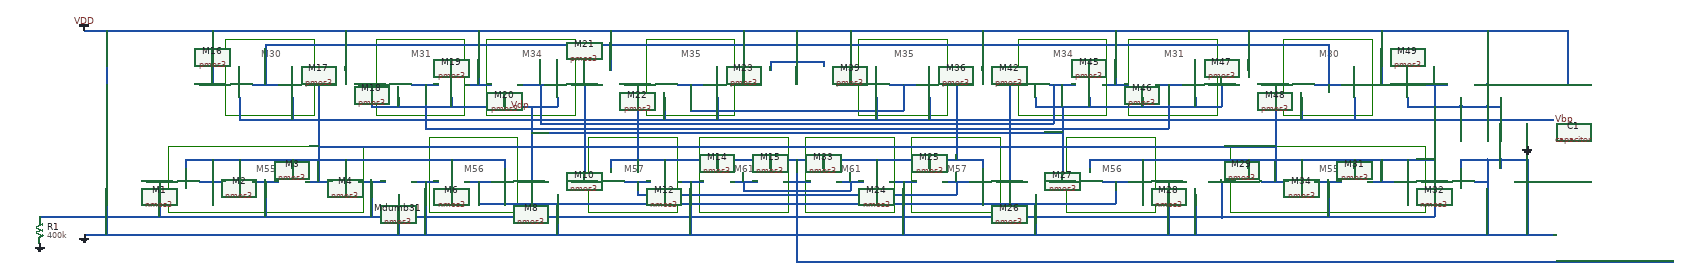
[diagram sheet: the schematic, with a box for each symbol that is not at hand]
v {xschem version=2.9.9 file_version=1.2 }
G {}
K {}
V {}
S {}
E {}
L 4 -700 -70 -500 -70 {}
L 4 -500 -240 -500 -70 {}
L 4 -700 -240 -500 -240 {}
L 4 -700 -240 -700 -70 {}
L 4 500 -70 700 -70 {}
L 4 700 -240 700 -70 {}
L 4 500 -240 700 -240 {}
L 4 500 -240 500 -70 {}
L 4 750 -70 950 -70 {}
L 4 950 -240 950 -70 {}
L 4 750 -240 950 -240 {}
L 4 750 -240 750 -70 {}
L 4 -950 -70 -750 -70 {}
L 4 -750 -240 -750 -70 {}
L 4 -950 -240 -750 -240 {}
L 4 -950 -240 -950 -70 {}
L 4 -1290 -70 -1090 -70 {}
L 4 -1090 -240 -1090 -70 {}
L 4 -1290 -240 -1090 -240 {}
L 4 -1290 -240 -1290 -70 {}
L 4 140 -70 340 -70 {}
L 4 340 -240 340 -70 {}
L 4 140 -240 340 -240 {}
L 4 140 -240 140 -70 {}
L 4 20 150 220 150 {}
L 4 220 -20 220 150 {}
L 4 20 -20 220 -20 {}
L 4 20 -20 20 150 {}
L 4 -220 150 -20 150 {}
L 4 -20 -20 -20 150 {}
L 4 -220 -20 -20 -20 {}
L 4 -220 -20 -220 150 {}
L 4 -470 150 -270 150 {}
L 4 -270 -20 -270 150 {}
L 4 -470 -20 -270 -20 {}
L 4 -470 -20 -470 150 {}
L 4 1100 -70 1300 -70 {}
L 4 1300 -240 1300 -70 {}
L 4 1100 -240 1300 -240 {}
L 4 1100 -240 1100 -70 {}
L 4 -1420 0 -1420 150 {}
L 4 -1420 150 -980 150 {}
L 4 -980 0 -980 150 {}
L 4 -1420 0 -980 0 {}
L 4 980 0 980 150 {}
L 4 980 150 1420 150 {}
L 4 1420 0 1420 150 {}
L 4 980 0 1420 0 {}
L 4 -830 150 -630 150 {}
L 4 -630 -20 -630 150 {}
L 4 -830 -20 -630 -20 {}
L 4 -830 -20 -830 150 {}
L 4 610 150 810 150 {}
L 4 810 -20 810 150 {}
L 4 610 -20 810 -20 {}
L 4 610 -20 610 150 {}
L 4 -340 -70 -140 -70 {}
L 4 -140 -240 -140 -70 {}
L 4 -340 -240 -140 -240 {}
L 4 -340 -240 -340 -70 {}
L 4 260 150 460 150 {}
L 4 460 -20 460 150 {}
L 4 260 -20 460 -20 {}
L 4 260 -20 260 150 {}
T {M34} -620 -220 0 0 0.4 0.4 {}
T {M34} 580 -220 0 0 0.4 0.4 {}
T {M31} 830 -220 0 0 0.4 0.4 {}
T {M31} -870 -220 0 0 0.4 0.4 {}
T {M30} -1210 -220 0 0 0.4 0.4 {}
T {M35} 220 -220 0 0 0.4 0.4 {}
T {M30} 1180 -220 0 0 0.4 0.4 {}
T {M55} -1220 40 0 0 0.4 0.4 {}
T {M55} 1180 40 0 0 0.4 0.4 {}
T {M56} -750 40 0 0 0.4 0.4 {}
T {M56} 690 40 0 0 0.4 0.4 {}
T {M35} -260 -220 0 0 0.4 0.4 {}
T {M57} 340 40 0 0 0.4 0.4 {}
T {M57} -390 40 0 0 0.4 0.4 {}
T {M61} -140 40 0 0 0.4 0.4 {}
T {M61} 100 40 0 0 0.4 0.4 {}
N -1020 30 -1020 50 { lab=#net1}
N -1140 30 -1140 50 { lab=#net1}
N -1260 30 -1260 50 { lab=#net1}
N -1380 30 -1380 50 { lab=#net1}
N -1350 80 -1290 80 { lab=#net1}
N -1230 80 -1170 80 { lab=#net2}
N -1110 80 -1050 80 { lab=#net1}
N -1230 -140 -1170 -140 { lab=#net3}
N -870 -140 -810 -140 { lab=#net4}
N -630 -140 -570 -140 { lab=#net5}
N -270 -140 -210 -140 { lab=#net6}
N -900 -110 -900 -90 { lab=Vdp}
N -540 -110 -540 -90 { lab=Vdp}
N -780 -110 -780 -90 { lab=Vdp}
N -660 -110 -660 -90 { lab=Vdp}
N -1260 -110 -1260 -60 { lab=Vbp}
N -180 -110 -180 -60 { lab=Vbp}
N -300 -110 -300 -60 { lab=Vbp}
N -1140 -110 -1140 -60 { lab=Vbp}
N -1320 -260 -1320 -140 { lab=VDD}
N -120 -260 -120 -140 { lab=VDD}
N -750 -140 -690 -140 { lab=VDD}
N -720 -260 -720 -140 { lab=VDD}
N -780 30 -780 50 { lab=#net1}
N -660 30 -660 50 { lab=#net1}
N -750 80 -690 80 { lab=#net7}
N -390 80 -330 80 { lab=#net8}
N -150 80 -90 80 { lab=#net9}
N -960 80 -960 160 { lab=#net2}
N -420 30 -420 50 { lab=#net10}
N -60 30 -60 50 { lab=#net10}
N -180 30 -180 50 { lab=#net10}
N -300 30 -300 50 { lab=#net10}
N -270 80 -210 80 { lab=GND}
N -240 80 -240 200 { lab=GND}
N -840 80 -840 200 { lab=GND}
N 0 30 0 80 { lab=#net10}
N -480 -60 -480 80 { lab=Vbp}
N -1110 -140 -1050 -140 { lab=#net1}
N -990 -140 -930 -140 { lab=Vdp}
N -1080 -140 -1080 30 { lab=#net1}
N -390 -140 -330 -140 { lab=#net10}
N -360 -140 -360 30 { lab=#net10}
N -510 -140 -450 -140 { lab=Vbp}
N -480 -140 -480 -60 { lab=Vbp}
N -870 80 -810 80 { lab=GND}
N -990 80 -930 80 { lab=#net2}
N -630 80 -570 80 { lab=Vdp}
N -600 -90 -600 80 { lab=Vdp}
N -510 80 -450 80 { lab=Vbp}
N 60 30 60 50 { lab=#net10}
N 180 30 180 50 { lab=#net10}
N 300 30 300 50 { lab=#net10}
N 420 30 420 50 { lab=#net10}
N -30 80 30 80 { lab=#net10}
N -420 30 420 30 { lab=#net10}
N 90 80 150 80 { lab=#net9}
N 210 80 270 80 { lab=GND}
N 330 80 390 80 { lab=#net8}
N 240 80 240 200 { lab=GND}
N -150 -140 -90 -140 { lab=VDD}
N 0 -260 0 -140 { lab=VDD}
N 90 -140 150 -140 { lab=VDD}
N 120 -260 120 -140 { lab=VDD}
N 180 -110 180 -60 { lab=Vbp}
N 300 -110 300 -60 { lab=Vbp}
N 1260 -110 1260 -60 { lab=Vbp}
N 1140 -110 1140 -60 { lab=Vbp}
N 540 -110 540 -90 { lab=Vdp}
N 660 -110 660 -90 { lab=Vdp}
N 780 -110 780 -90 { lab=Vdp}
N 900 -110 900 -90 { lab=Vdp}
N -960 -140 -960 -90 { lab=Vdp}
N -960 -90 -540 -90 { lab=Vdp}
N 210 -140 270 -140 { lab=#net6}
N 330 -140 390 -140 { lab=#net10}
N 450 -140 510 -140 { lab=Vbp}
N 570 -140 630 -140 { lab=#net5}
N 690 -140 750 -140 { lab=VDD}
N 810 -140 870 -140 { lab=#net4}
N 930 -140 990 -140 { lab=Vdp}
N 1050 -140 1110 -140 { lab=#net1}
N 1170 -140 1230 -140 { lab=#net3}
N 450 80 510 80 { lab=Vbp}
N 570 80 630 80 { lab=Vdp}
N 690 80 750 80 { lab=#net7}
N 810 80 870 80 { lab=GND}
N 930 80 990 80 { lab=#net2}
N 1050 80 1110 80 { lab=#net1}
N 1170 80 1230 80 { lab=#net2}
N 1290 80 1350 80 { lab=#net1}
N 1380 30 1380 50 { lab=#net1}
N 1020 30 1020 50 { lab=#net1}
N 1140 30 1140 50 { lab=#net1}
N 1260 30 1260 50 { lab=#net1}
N -1260 -60 1260 -60 { lab=Vbp}
N 960 -140 960 -90 { lab=Vdp}
N 540 -90 960 -90 { lab=Vdp}
N 360 -140 360 30 { lab=#net10}
N 480 -140 480 -60 { lab=Vbp}
N 480 -60 480 80 { lab=Vbp}
N 840 80 840 200 { lab=GND}
N 960 80 960 160 { lab=#net2}
N 600 -90 600 80 { lab=Vdp}
N 660 30 660 50 { lab=#net1}
N 780 30 780 50 { lab=#net1}
N 660 30 1440 30 { lab=#net1}
N 1320 -260 1320 -140 { lab=VDD}
N 1080 -140 1080 30 { lab=#net1}
N -600 -30 600 -30 { lab=Vdp}
N -1080 0 1080 0 { lab=#net1}
N 0 80 0 260 { lab=#net10}
N -1350 -140 -1290 -140 { lab=VDD}
N -1470 80 -1410 80 { lab=#net2}
N 1410 80 1470 80 { lab=#net2}
N 1500 30 1500 50 { lab=GND}
N 1500 30 1560 30 { lab=GND}
N 1560 30 1560 80 { lab=GND}
N 1530 80 1560 80 { lab=GND}
N 1560 80 1560 200 { lab=GND}
N 1290 -140 1350 -140 { lab=VDD}
N 1380 -110 1380 -90 { lab=VDD}
N 1380 -90 1500 -90 { lab=VDD}
N 1500 -110 1500 -90 { lab=VDD}
N 1410 -140 1470 -140 { lab=VDD}
N 1440 -140 1440 -90 { lab=VDD}
N 1530 -140 1560 -140 { lab=VDD}
N 1560 -260 1560 -140 { lab=VDD}
N -1610 160 960 160 { lab=#net2}
N -1610 200 1710 200 { lab=GND}
N 0 260 1710 260 { lab=#net10}
N 1260 -60 1710 -60 { lab=Vbp}
N -1610 -260 1710 -260 { lab=VDD}
N -900 110 -900 200 { lab=GND}
N -1020 -260 -1020 -170 { lab=VDD}
N -60 -190 -60 -170 { lab=VDD}
N 60 -190 60 -180 { lab=VDD}
N -60 -190 0 -190 { lab=VDD}
N 0 -190 60 -190 { lab=VDD}
N -420 -260 -420 -170 { lab=VDD}
N 420 -260 420 -170 { lab=VDD}
N 1020 -260 1020 -170 { lab=VDD}
N -540 110 -540 200 { lab=GND}
N -1560 -260 -1560 -140 { lab=VDD}
N -1560 80 -1560 200 { lab=GND}
N 1500 -90 1560 -90 { lab=VDD}
N 1560 -140 1560 -90 { lab=VDD}
N 900 110 900 200 { lab=GND}
N 540 110 540 200 { lab=GND}
N -1200 80 -1200 150 { lab=#net2}
N -1200 150 -1200 160 { lab=#net2}
N -1080 30 -1080 80 { lab=#net1}
N -1320 30 -1320 80 { lab=#net1}
N -1440 80 -1440 160 { lab=#net2}
N -1380 30 -660 30 { lab=#net1}
N 960 160 1440 160 { lab=#net2}
N 1440 80 1440 160 { lab=#net2}
N 1200 80 1200 160 { lab=#net2}
N 1080 30 1080 80 { lab=#net1}
N 1320 30 1320 80 { lab=#net1}
N 1710 260 1980 260 { lab=#net10}
N -1650 160 -1610 160 { lab=#net2}
N -1710 160 -1660 160 { lab=#net2}
N -840 -140 -840 -40 { lab=#net4}
N -840 -40 840 -40 { lab=#net4}
N 840 -140 840 -40 { lab=#net4}
N -580 -140 -580 -50 { lab=#net5}
N -580 -50 580 -50 { lab=#net5}
N 580 -140 580 -50 { lab=#net5}
N -240 -140 -240 -80 { lab=#net6}
N -240 -80 240 -80 { lab=#net6}
N 240 -140 240 -80 { lab=#net6}
N -1200 -230 -1200 -140 { lab=#net3}
N -1200 -230 1200 -230 { lab=#net3}
N 1200 -230 1200 -140 { lab=#net3}
N -720 80 -720 130 { lab=#net7}
N -720 130 720 130 { lab=#net7}
N 720 80 720 130 { lab=#net7}
N 360 80 360 110 { lab=#net8}
N -350 110 360 110 { lab=#net8}
N -360 110 -350 110 { lab=#net8}
N -360 80 -360 110 { lab=#net8}
N -120 80 -120 100 { lab=#net9}
N -120 100 120 100 { lab=#net9}
N 120 80 120 100 { lab=#net9}
N 720 -260 720 -140 { lab=VDD}
N 1560 30 1590 30 { lab=GND}
N 1590 30 1590 40 { lab=GND}
N 1590 40 1590 50 { lab=GND}
N 1590 30 1620 30 { lab=GND}
N 1620 80 1650 80 { lab=GND}
N 1620 30 1650 30 { lab=GND}
N 1650 30 1650 200 { lab=GND}
N -1660 160 -1650 160 { lab=#net2}
N 1590 -110 1590 -90 { lab=VDD}
N 1620 -140 1680 -140 { lab=VDD}
N 1740 -260 1740 -140 { lab=VDD}
N 1710 -260 1740 -260 { lab=VDD}
N 1560 -90 1590 -90 { lab=VDD}
N 1680 -140 1740 -140 { lab=VDD}
C {madvlsi/nmos3.sym} -1380 80 1 0 {name=M1
L=4.0
W=16
body=GND
nf=1
mult=1
ad="'int((nf+1)/2) * W/nf * 0.29'" 
pd="'2*int((nf+1)/2) * (W/nf + 0.29)'"
as="'int((nf+2)/2) * W/nf * 0.29'" 
ps="'2*int((nf+2)/2) * (W/nf + 0.29)'"
nrd="'0.29 / W'" nrs="'0.29 / W'"
sa=0 sb=0 sd=0
model=nfet_01v8
spiceprefix=X
}
C {madvlsi/nmos3.sym} -1260 80 1 0 {name=M2
L=4.0
W=16
body=GND
nf=1
mult=1
ad="'int((nf+1)/2) * W/nf * 0.29'" 
pd="'2*int((nf+1)/2) * (W/nf + 0.29)'"
as="'int((nf+2)/2) * W/nf * 0.29'" 
ps="'2*int((nf+2)/2) * (W/nf + 0.29)'"
nrd="'0.29 / W'" nrs="'0.29 / W'"
sa=0 sb=0 sd=0
model=nfet_01v8
spiceprefix=X
}
C {madvlsi/nmos3.sym} -1140 80 1 0 {name=M3
L=4.0
W=16
body=GND
nf=1
mult=1
ad="'int((nf+1)/2) * W/nf * 0.29'" 
pd="'2*int((nf+1)/2) * (W/nf + 0.29)'"
as="'int((nf+2)/2) * W/nf * 0.29'" 
ps="'2*int((nf+2)/2) * (W/nf + 0.29)'"
nrd="'0.29 / W'" nrs="'0.29 / W'"
sa=0 sb=0 sd=0
model=nfet_01v8
spiceprefix=X
}
C {madvlsi/nmos3.sym} -1020 80 1 0 {name=M4
L=4.0
W=16
body=GND
nf=1
mult=1
ad="'int((nf+1)/2) * W/nf * 0.29'" 
pd="'2*int((nf+1)/2) * (W/nf + 0.29)'"
as="'int((nf+2)/2) * W/nf * 0.29'" 
ps="'2*int((nf+2)/2) * (W/nf + 0.29)'"
nrd="'0.29 / W'" nrs="'0.29 / W'"
sa=0 sb=0 sd=0
model=nfet_01v8
spiceprefix=X
}
C {madvlsi/nmos3.sym} -780 80 1 0 {name=M6
L=4.0
W=16
body=GND
nf=1
mult=1
ad="'int((nf+1)/2) * W/nf * 0.29'" 
pd="'2*int((nf+1)/2) * (W/nf + 0.29)'"
as="'int((nf+2)/2) * W/nf * 0.29'" 
ps="'2*int((nf+2)/2) * (W/nf + 0.29)'"
nrd="'0.29 / W'" nrs="'0.29 / W'"
sa=0 sb=0 sd=0
model=nfet_01v8
spiceprefix=X
}
C {madvlsi/nmos3.sym} -660 80 1 0 {name=M8
L=4.0
W=16
body=GND
nf=1
mult=1
ad="'int((nf+1)/2) * W/nf * 0.29'" 
pd="'2*int((nf+1)/2) * (W/nf + 0.29)'"
as="'int((nf+2)/2) * W/nf * 0.29'" 
ps="'2*int((nf+2)/2) * (W/nf + 0.29)'"
nrd="'0.29 / W'" nrs="'0.29 / W'"
sa=0 sb=0 sd=0
model=nfet_01v8
spiceprefix=X
}
C {madvlsi/nmos3.sym} -420 80 1 0 {name=M10
L=4.0
W=16
body=GND
nf=1
mult=1
ad="'int((nf+1)/2) * W/nf * 0.29'" 
pd="'2*int((nf+1)/2) * (W/nf + 0.29)'"
as="'int((nf+2)/2) * W/nf * 0.29'" 
ps="'2*int((nf+2)/2) * (W/nf + 0.29)'"
nrd="'0.29 / W'" nrs="'0.29 / W'"
sa=0 sb=0 sd=0
model=nfet_01v8
spiceprefix=X
}
C {madvlsi/nmos3.sym} -300 80 1 0 {name=M12
L=4.0
W=16
body=GND
nf=1
mult=1
ad="'int((nf+1)/2) * W/nf * 0.29'" 
pd="'2*int((nf+1)/2) * (W/nf + 0.29)'"
as="'int((nf+2)/2) * W/nf * 0.29'" 
ps="'2*int((nf+2)/2) * (W/nf + 0.29)'"
nrd="'0.29 / W'" nrs="'0.29 / W'"
sa=0 sb=0 sd=0
model=nfet_01v8
spiceprefix=X
}
C {madvlsi/nmos3.sym} -180 80 1 0 {name=M14
L=4.0
W=16
body=GND
nf=1
mult=1
ad="'int((nf+1)/2) * W/nf * 0.29'" 
pd="'2*int((nf+1)/2) * (W/nf + 0.29)'"
as="'int((nf+2)/2) * W/nf * 0.29'" 
ps="'2*int((nf+2)/2) * (W/nf + 0.29)'"
nrd="'0.29 / W'" nrs="'0.29 / W'"
sa=0 sb=0 sd=0
model=nfet_01v8
spiceprefix=X
}
C {madvlsi/nmos3.sym} -60 80 1 0 {name=M15
L=4.0
W=16
body=GND
nf=1
mult=1
ad="'int((nf+1)/2) * W/nf * 0.29'" 
pd="'2*int((nf+1)/2) * (W/nf + 0.29)'"
as="'int((nf+2)/2) * W/nf * 0.29'" 
ps="'2*int((nf+2)/2) * (W/nf + 0.29)'"
nrd="'0.29 / W'" nrs="'0.29 / W'"
sa=0 sb=0 sd=0
model=nfet_01v8
spiceprefix=X
}
C {madvlsi/pmos3.sym} -1260 -140 1 1 {name=M16
L=4.0
W=16
body=VDD
nf=1
mult=1
ad="'int((nf+1)/2) * W/nf * 0.29'" 
pd="'2*int((nf+1)/2) * (W/nf + 0.29)'"
as="'int((nf+2)/2) * W/nf * 0.29'" 
ps="'2*int((nf+2)/2) * (W/nf + 0.29)'"
nrd="'0.29 / W'" nrs="'0.29 / W'"
sa=0 sb=0 sd=0
model=pfet_01v8
spiceprefix=X
}
C {madvlsi/pmos3.sym} -1140 -140 1 1 {name=M17
L=4.0
W=16
body=VDD
nf=1
mult=1
ad="'int((nf+1)/2) * W/nf * 0.29'" 
pd="'2*int((nf+1)/2) * (W/nf + 0.29)'"
as="'int((nf+2)/2) * W/nf * 0.29'" 
ps="'2*int((nf+2)/2) * (W/nf + 0.29)'"
nrd="'0.29 / W'" nrs="'0.29 / W'"
sa=0 sb=0 sd=0
model=pfet_01v8
spiceprefix=X
}
C {madvlsi/pmos3.sym} -900 -140 1 1 {name=M18
L=4.0
W=16
body=VDD
nf=1
mult=1
ad="'int((nf+1)/2) * W/nf * 0.29'" 
pd="'2*int((nf+1)/2) * (W/nf + 0.29)'"
as="'int((nf+2)/2) * W/nf * 0.29'" 
ps="'2*int((nf+2)/2) * (W/nf + 0.29)'"
nrd="'0.29 / W'" nrs="'0.29 / W'"
sa=0 sb=0 sd=0
model=pfet_01v8
spiceprefix=X
}
C {madvlsi/pmos3.sym} -780 -140 1 1 {name=M19
L=4.0
W=16
body=VDD
nf=1
mult=1
ad="'int((nf+1)/2) * W/nf * 0.29'" 
pd="'2*int((nf+1)/2) * (W/nf + 0.29)'"
as="'int((nf+2)/2) * W/nf * 0.29'" 
ps="'2*int((nf+2)/2) * (W/nf + 0.29)'"
nrd="'0.29 / W'" nrs="'0.29 / W'"
sa=0 sb=0 sd=0
model=pfet_01v8
spiceprefix=X
}
C {madvlsi/pmos3.sym} -660 -140 1 1 {name=M20
L=4.0
W=16
body=VDD
nf=1
mult=1
ad="'int((nf+1)/2) * W/nf * 0.29'" 
pd="'2*int((nf+1)/2) * (W/nf + 0.29)'"
as="'int((nf+2)/2) * W/nf * 0.29'" 
ps="'2*int((nf+2)/2) * (W/nf + 0.29)'"
nrd="'0.29 / W'" nrs="'0.29 / W'"
sa=0 sb=0 sd=0
model=pfet_01v8
spiceprefix=X
}
C {madvlsi/pmos3.sym} -540 -140 1 1 {name=M21
L=4.0
W=16
body=VDD
nf=1
mult=1
ad="'int((nf+1)/2) * W/nf * 0.29'" 
pd="'2*int((nf+1)/2) * (W/nf + 0.29)'"
as="'int((nf+2)/2) * W/nf * 0.29'" 
ps="'2*int((nf+2)/2) * (W/nf + 0.29)'"
nrd="'0.29 / W'" nrs="'0.29 / W'"
sa=0 sb=0 sd=0
model=pfet_01v8
spiceprefix=X
}
C {madvlsi/pmos3.sym} -300 -140 1 1 {name=M22
L=4.0
W=16
body=VDD
nf=1
mult=1
ad="'int((nf+1)/2) * W/nf * 0.29'" 
pd="'2*int((nf+1)/2) * (W/nf + 0.29)'"
as="'int((nf+2)/2) * W/nf * 0.29'" 
ps="'2*int((nf+2)/2) * (W/nf + 0.29)'"
nrd="'0.29 / W'" nrs="'0.29 / W'"
sa=0 sb=0 sd=0
model=pfet_01v8
spiceprefix=X
}
C {madvlsi/pmos3.sym} -180 -140 1 1 {name=M23
L=4.0
W=16
body=VDD
nf=1
mult=1
ad="'int((nf+1)/2) * W/nf * 0.29'" 
pd="'2*int((nf+1)/2) * (W/nf + 0.29)'"
as="'int((nf+2)/2) * W/nf * 0.29'" 
ps="'2*int((nf+2)/2) * (W/nf + 0.29)'"
nrd="'0.29 / W'" nrs="'0.29 / W'"
sa=0 sb=0 sd=0
model=pfet_01v8
spiceprefix=X
}
C {madvlsi/nmos3.sym} -900 80 3 0 {name=Mdumb31
L=4.0
W=16
body=GND
nf=1
mult=1
ad="'int((nf+1)/2) * W/nf * 0.29'" 
pd="'2*int((nf+1)/2) * (W/nf + 0.29)'"
as="'int((nf+2)/2) * W/nf * 0.29'" 
ps="'2*int((nf+2)/2) * (W/nf + 0.29)'"
nrd="'0.29 / W'" nrs="'0.29 / W'"
sa=0 sb=0 sd=0
model=nfet_01v8
spiceprefix=X
}
C {madvlsi/nmos3.sym} 60 80 1 0 {name=M33
L=4.0
W=16
body=GND
nf=1
mult=1
ad="'int((nf+1)/2) * W/nf * 0.29'" 
pd="'2*int((nf+1)/2) * (W/nf + 0.29)'"
as="'int((nf+2)/2) * W/nf * 0.29'" 
ps="'2*int((nf+2)/2) * (W/nf + 0.29)'"
nrd="'0.29 / W'" nrs="'0.29 / W'"
sa=0 sb=0 sd=0
model=nfet_01v8
spiceprefix=X
}
C {madvlsi/nmos3.sym} 180 80 1 0 {name=M24
L=4.0
W=16
body=GND
nf=1
mult=1
ad="'int((nf+1)/2) * W/nf * 0.29'" 
pd="'2*int((nf+1)/2) * (W/nf + 0.29)'"
as="'int((nf+2)/2) * W/nf * 0.29'" 
ps="'2*int((nf+2)/2) * (W/nf + 0.29)'"
nrd="'0.29 / W'" nrs="'0.29 / W'"
sa=0 sb=0 sd=0
model=nfet_01v8
spiceprefix=X
}
C {madvlsi/nmos3.sym} 300 80 1 0 {name=M25
L=4.0
W=16
body=GND
nf=1
mult=1
ad="'int((nf+1)/2) * W/nf * 0.29'" 
pd="'2*int((nf+1)/2) * (W/nf + 0.29)'"
as="'int((nf+2)/2) * W/nf * 0.29'" 
ps="'2*int((nf+2)/2) * (W/nf + 0.29)'"
nrd="'0.29 / W'" nrs="'0.29 / W'"
sa=0 sb=0 sd=0
model=nfet_01v8
spiceprefix=X
}
C {madvlsi/nmos3.sym} 420 80 1 0 {name=M26
L=4.0
W=16
body=GND
nf=1
mult=1
ad="'int((nf+1)/2) * W/nf * 0.29'" 
pd="'2*int((nf+1)/2) * (W/nf + 0.29)'"
as="'int((nf+2)/2) * W/nf * 0.29'" 
ps="'2*int((nf+2)/2) * (W/nf + 0.29)'"
nrd="'0.29 / W'" nrs="'0.29 / W'"
sa=0 sb=0 sd=0
model=nfet_01v8
spiceprefix=X
}
C {madvlsi/nmos3.sym} 660 80 1 0 {name=M27
L=4.0
W=16
body=GND
nf=1
mult=1
ad="'int((nf+1)/2) * W/nf * 0.29'" 
pd="'2*int((nf+1)/2) * (W/nf + 0.29)'"
as="'int((nf+2)/2) * W/nf * 0.29'" 
ps="'2*int((nf+2)/2) * (W/nf + 0.29)'"
nrd="'0.29 / W'" nrs="'0.29 / W'"
sa=0 sb=0 sd=0
model=nfet_01v8
spiceprefix=X
}
C {madvlsi/nmos3.sym} 780 80 1 0 {name=M28
L=4.0
W=16
body=GND
nf=1
mult=1
ad="'int((nf+1)/2) * W/nf * 0.29'" 
pd="'2*int((nf+1)/2) * (W/nf + 0.29)'"
as="'int((nf+2)/2) * W/nf * 0.29'" 
ps="'2*int((nf+2)/2) * (W/nf + 0.29)'"
nrd="'0.29 / W'" nrs="'0.29 / W'"
sa=0 sb=0 sd=0
model=nfet_01v8
spiceprefix=X
}
C {madvlsi/nmos3.sym} 1020 80 1 0 {name=M29
L=4.0
W=16
body=GND
nf=1
mult=1
ad="'int((nf+1)/2) * W/nf * 0.29'" 
pd="'2*int((nf+1)/2) * (W/nf + 0.29)'"
as="'int((nf+2)/2) * W/nf * 0.29'" 
ps="'2*int((nf+2)/2) * (W/nf + 0.29)'"
nrd="'0.29 / W'" nrs="'0.29 / W'"
sa=0 sb=0 sd=0
model=nfet_01v8
spiceprefix=X
}
C {madvlsi/nmos3.sym} 1140 80 1 0 {name=M34
L=4.0
W=16
body=GND
nf=1
mult=1
ad="'int((nf+1)/2) * W/nf * 0.29'" 
pd="'2*int((nf+1)/2) * (W/nf + 0.29)'"
as="'int((nf+2)/2) * W/nf * 0.29'" 
ps="'2*int((nf+2)/2) * (W/nf + 0.29)'"
nrd="'0.29 / W'" nrs="'0.29 / W'"
sa=0 sb=0 sd=0
model=nfet_01v8
spiceprefix=X
}
C {madvlsi/nmos3.sym} 1260 80 1 0 {name=M31
L=4.0
W=16
body=GND
nf=1
mult=1
ad="'int((nf+1)/2) * W/nf * 0.29'" 
pd="'2*int((nf+1)/2) * (W/nf + 0.29)'"
as="'int((nf+2)/2) * W/nf * 0.29'" 
ps="'2*int((nf+2)/2) * (W/nf + 0.29)'"
nrd="'0.29 / W'" nrs="'0.29 / W'"
sa=0 sb=0 sd=0
model=nfet_01v8
spiceprefix=X
}
C {madvlsi/nmos3.sym} 1380 80 1 0 {name=M32
L=4.0
W=16
body=GND
nf=1
mult=1
ad="'int((nf+1)/2) * W/nf * 0.29'" 
pd="'2*int((nf+1)/2) * (W/nf + 0.29)'"
as="'int((nf+2)/2) * W/nf * 0.29'" 
ps="'2*int((nf+2)/2) * (W/nf + 0.29)'"
nrd="'0.29 / W'" nrs="'0.29 / W'"
sa=0 sb=0 sd=0
model=nfet_01v8
spiceprefix=X
}
C {madvlsi/pmos3.sym} 180 -140 1 1 {name=M39
L=4.0
W=16
body=VDD
nf=1
mult=1
ad="'int((nf+1)/2) * W/nf * 0.29'" 
pd="'2*int((nf+1)/2) * (W/nf + 0.29)'"
as="'int((nf+2)/2) * W/nf * 0.29'" 
ps="'2*int((nf+2)/2) * (W/nf + 0.29)'"
nrd="'0.29 / W'" nrs="'0.29 / W'"
sa=0 sb=0 sd=0
model=pfet_01v8
spiceprefix=X
}
C {madvlsi/pmos3.sym} 300 -140 1 1 {name=M36
L=4.0
W=16
body=VDD
nf=1
mult=1
ad="'int((nf+1)/2) * W/nf * 0.29'" 
pd="'2*int((nf+1)/2) * (W/nf + 0.29)'"
as="'int((nf+2)/2) * W/nf * 0.29'" 
ps="'2*int((nf+2)/2) * (W/nf + 0.29)'"
nrd="'0.29 / W'" nrs="'0.29 / W'"
sa=0 sb=0 sd=0
model=pfet_01v8
spiceprefix=X
}
C {madvlsi/pmos3.sym} 540 -140 1 1 {name=M42
L=4.0
W=16
body=VDD
nf=1
mult=1
ad="'int((nf+1)/2) * W/nf * 0.29'" 
pd="'2*int((nf+1)/2) * (W/nf + 0.29)'"
as="'int((nf+2)/2) * W/nf * 0.29'" 
ps="'2*int((nf+2)/2) * (W/nf + 0.29)'"
nrd="'0.29 / W'" nrs="'0.29 / W'"
sa=0 sb=0 sd=0
model=pfet_01v8
spiceprefix=X
}
C {madvlsi/pmos3.sym} 660 -140 1 1 {name=M45
L=4.0
W=16
body=VDD
nf=1
mult=1
ad="'int((nf+1)/2) * W/nf * 0.29'" 
pd="'2*int((nf+1)/2) * (W/nf + 0.29)'"
as="'int((nf+2)/2) * W/nf * 0.29'" 
ps="'2*int((nf+2)/2) * (W/nf + 0.29)'"
nrd="'0.29 / W'" nrs="'0.29 / W'"
sa=0 sb=0 sd=0
model=pfet_01v8
spiceprefix=X
}
C {madvlsi/pmos3.sym} 780 -140 1 1 {name=M46
L=4.0
W=16
body=VDD
nf=1
mult=1
ad="'int((nf+1)/2) * W/nf * 0.29'" 
pd="'2*int((nf+1)/2) * (W/nf + 0.29)'"
as="'int((nf+2)/2) * W/nf * 0.29'" 
ps="'2*int((nf+2)/2) * (W/nf + 0.29)'"
nrd="'0.29 / W'" nrs="'0.29 / W'"
sa=0 sb=0 sd=0
model=pfet_01v8
spiceprefix=X
}
C {madvlsi/pmos3.sym} 900 -140 1 1 {name=M47
L=4.0
W=16
body=VDD
nf=1
mult=1
ad="'int((nf+1)/2) * W/nf * 0.29'" 
pd="'2*int((nf+1)/2) * (W/nf + 0.29)'"
as="'int((nf+2)/2) * W/nf * 0.29'" 
ps="'2*int((nf+2)/2) * (W/nf + 0.29)'"
nrd="'0.29 / W'" nrs="'0.29 / W'"
sa=0 sb=0 sd=0
model=pfet_01v8
spiceprefix=X
}
C {madvlsi/pmos3.sym} 1140 -140 1 1 {name=M48
L=4.0
W=16
body=VDD
nf=1
mult=1
ad="'int((nf+1)/2) * W/nf * 0.29'" 
pd="'2*int((nf+1)/2) * (W/nf + 0.29)'"
as="'int((nf+2)/2) * W/nf * 0.29'" 
ps="'2*int((nf+2)/2) * (W/nf + 0.29)'"
nrd="'0.29 / W'" nrs="'0.29 / W'"
sa=0 sb=0 sd=0
model=pfet_01v8
spiceprefix=X
}
C {madvlsi/pmos3.sym} 1260 -140 1 1 {name=M49
L=4.0
W=16
body=VDD
nf=1
mult=1
ad="'int((nf+1)/2) * W/nf * 0.29'" 
pd="'2*int((nf+1)/2) * (W/nf + 0.29)'"
as="'int((nf+2)/2) * W/nf * 0.29'" 
ps="'2*int((nf+2)/2) * (W/nf + 0.29)'"
nrd="'0.29 / W'" nrs="'0.29 / W'"
sa=0 sb=0 sd=0
model=pfet_01v8
spiceprefix=X
}
C {madvlsi/gnd.sym} -1610 200 1 0 {name=l2 lab=GND}
C {madvlsi/vdd.sym} -1610 -260 3 0 {name=l3 lab=VDD}
C {devices/lab_pin.sym} -600 -90 1 0 {name=l4 sig_type=std_logic lab=Vdp}
C {madvlsi/resistor.sym} -1710 190 0 0 {name=R1
value=400k
m=1}
C {madvlsi/gnd.sym} -1710 220 0 0 {name=l26 lab=GND}
C {devices/lab_pin.sym} 1710 -60 2 0 {name=l63 sig_type=std_logic lab=Vbp}
C {madvlsi/capacitor.sym} 1650 -30 0 0 {name=C1
value=10p
m=1}
C {madvlsi/gnd.sym} 1650 0 0 0 {name=l64 lab=GND}
